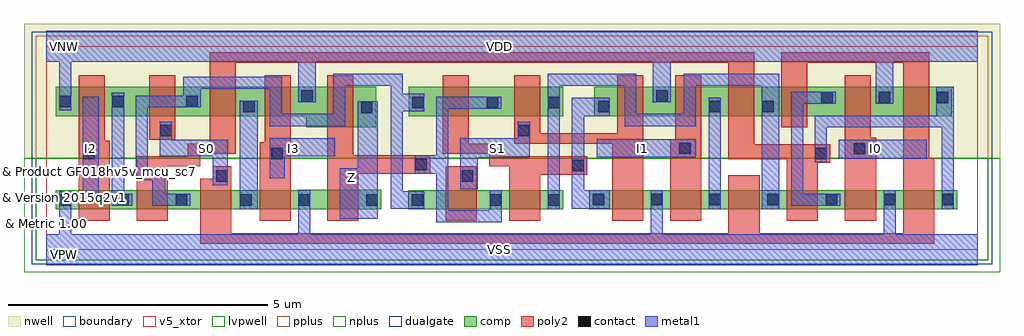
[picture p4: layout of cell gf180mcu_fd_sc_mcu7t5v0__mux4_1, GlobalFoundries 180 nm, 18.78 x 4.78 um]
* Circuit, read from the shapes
.subckt gf180mcu_fd_sc_mcu7t5v0__mux4_1 I0 I1 I2 I3 S0 S1 VDD VNW VSS Z
XM1 n1 I2 VSS VSUBS nfet_05v0 w=0.365u l=0.6u
XM2 n2 n3 n1 VSUBS nfet_05v0 w=0.365u l=0.6u
XM3 n4 S0 n2 VSUBS nfet_05v0 w=0.365u l=0.6u
XM4 VSS I3 n4 VSUBS nfet_05v0 w=0.365u l=0.6u
XM5 Z n5 VSS VSUBS nfet_05v0 w=0.38u l=0.6u
XM6 n5 S1 n2 VSUBS nfet_05v0 w=0.365u l=0.6u
XM7 n6 n7 n5 VSUBS nfet_05v0 w=0.365u l=0.6u
XM8 VSS S1 n7 VSUBS nfet_05v0 w=0.365u l=0.6u
XM9 n8 I1 VSS VSUBS nfet_05v0 w=0.365u l=0.6u
XM10 n6 S0 n8 VSUBS nfet_05v0 w=0.365u l=0.6u
XM11 n9 n3 n6 VSUBS nfet_05v0 w=0.365u l=0.6u
XM12 VSS I0 n9 VSUBS nfet_05v0 w=0.365u l=0.6u
XM13 n3 S0 VSS VSUBS nfet_05v0 w=0.365u l=0.6u
XM14 n1 I2 VDD VNW pfet_05v0 w=0.565u l=0.5u
XM15 n2 S0 n1 VNW pfet_05v0 w=0.565u l=0.5u
XM16 n4 n3 n2 VNW pfet_05v0 w=0.565u l=0.5u
XM17 VDD I3 n4 VNW pfet_05v0 w=0.565u l=0.5u
XM18 Z n5 VDD VNW pfet_05v0 w=0.78u l=0.5u
XM19 n5 n7 n2 VNW pfet_05v0 w=0.565u l=0.5u
XM20 n6 S1 n5 VNW pfet_05v0 w=0.565u l=0.5u
XM21 VDD S1 n7 VNW pfet_05v0 w=0.565u l=0.5u
XM22 n8 I1 VDD VNW pfet_05v0 w=0.565u l=0.5u
XM23 n6 n3 n8 VNW pfet_05v0 w=0.565u l=0.5u
XM24 n9 S0 n6 VNW pfet_05v0 w=0.565u l=0.5u
XM25 VDD I0 n9 VNW pfet_05v0 w=0.565u l=0.5u
XM26 n3 S0 VDD VNW pfet_05v0 w=0.565u l=0.5u
.ends

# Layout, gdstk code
import gdstk
lib = gdstk.Library(unit=1e-6, precision=1e-09)
def R(c, l, rs):  # rectangles x0, y0, x1, y1
    for r in rs: c.add(gdstk.rectangle(r[:2], r[2:], *l))
def A(c, l, x, y, w, h, nx, ny, dx, dy):  # array of equal rectangles
    R(c, l, [(x+i*dx, y+j*dy, x+i*dx+w, y+j*dy+h) for i in range(nx) for j in range(ny)])
def P(c, l, *ps):  # polygons
    for p in ps: c.add(gdstk.Polygon(p, *l))
boundary = (0, 0)
nwell = (21, 0)
comp = (22, 0)
poly2 = (30, 0)
pplus = (31, 0)
nplus = (32, 0)
contact = (33, 0)
metal1 = (34, 0)
dualgate = (55, 0)
v5_xtor = (112, 1)
lvpwell = (204, 0)

gf180mcu_fd_sc_mcu7t5v0_ = lib.new_cell('gf180mcu_fd_sc_mcu7t5v0__mux4_1')
R(gf180mcu_fd_sc_mcu7t5v0_, boundary, [(0,0,17.92,3.92)])
R(gf180mcu_fd_sc_mcu7t5v0_, nwell, [(-0.43,1.76,18.35,4.35)])
R(gf180mcu_fd_sc_mcu7t5v0_, comp, [(6.96,0.78,9.945,1.145), (10.445,0.78,17.525,1.145), (6.975,2.575,9.945,3.14), (10.545,2.575,17.425,3.14)])
P(gf180mcu_fd_sc_mcu7t5v0_, comp, [(5.005,2.36),(5.005,2.575),(0.18,2.575),(0.18,3.14),(6.345,3.14),(6.345,2.36)],
  [(0.18,0.78),(0.18,1.145),(5.005,1.145),(5.005,1.16),(6.445,1.16),(6.445,0.78)])
R(gf180mcu_fd_sc_mcu7t5v0_, poly2, [(7.685,0.56,8.285,1.605), (1.98,2.115,2.48,3.36)])
P(gf180mcu_fd_sc_mcu7t5v0_, poly2, [(0.62,0.56),(0.62,3.36),(1.12,3.36),(1.12,2.1),(1.22,2.1),(1.22,0.56)],
  [(4.105,0.56),(4.105,2.075),(4.205,2.075),(4.205,3.36),(4.705,3.36),(4.705,0.56)],
  [(5.405,0.56),(5.405,3.36),(5.905,3.36),(5.905,1.82),(7.385,1.82),(7.385,1.46),(6.005,1.46),(6.005,0.56)],
  [(8.905,0.56),(8.905,1.605),(8.525,1.605),(8.525,1.845),(7.625,1.845),(7.625,3.36),(8.125,3.36),(8.125,2.045),(8.765,2.045),(8.765,1.805),(10.41,1.805),(10.41,1.445),(9.505,1.445),(9.505,0.56)],
  [(10.885,0.56),(10.885,2.045),(9.005,2.045),(9.005,3.36),(9.505,3.36),(9.505,2.245),(10.985,2.245),(10.985,3.36),(11.485,3.36),(11.485,0.56)],
  [(12.005,0.56),(12.005,2.13),(12.105,2.13),(12.105,3.36),(12.605,3.36),(12.605,0.56)],
  [(1.74,0.56),(1.74,1.805),(2.72,1.805),(2.72,2.045),(3.14,2.045),(3.14,3.8),(13.625,3.8),(13.625,2.035),(15.085,2.035),(15.085,1.675),(14.845,1.675),(14.845,0.56),(14.245,0.56),(14.245,1.74),(13.125,1.74),(13.125,3.6),(3.64,3.6),(3.64,1.845),(2.96,1.845),(2.96,1.605),(2.34,1.605),(2.34,0.56)],
  [(15.365,0.56),(15.365,3.36),(15.865,3.36),(15.865,2.155),(15.965,2.155),(15.965,0.56)],
  [(2.96,0.12),(2.96,1.365),(3.2,1.365),(3.2,1.605),(3.56,1.605),(3.56,0.32),(13.125,0.32),(13.125,1.44),(13.725,1.44),(13.725,0.32),(16.485,0.32),(16.485,3.6),(14.645,3.6),(14.645,2.355),(14.145,2.355),(14.145,3.8),(16.985,3.8),(16.985,1.775),(17.085,1.775),(17.085,0.12)])
R(gf180mcu_fd_sc_mcu7t5v0_, pplus, [(-0.2,1.76,18.12,4.12)])
R(gf180mcu_fd_sc_mcu7t5v0_, nplus, [(-0.2,-0.2,18.12,1.76)])
A(gf180mcu_fd_sc_mcu7t5v0_, contact, 0.25, 0.85, 0.22, 0.22, 3, 1, 1.12, 0)
A(gf180mcu_fd_sc_mcu7t5v0_, contact, 10.515, 0.855, 0.22, 0.22, 7, 1, 1.12, 0)
R(gf180mcu_fd_sc_mcu7t5v0_, contact, [(3.735,0.85,3.955,1.07), (4.855,0.85,5.075,1.07), (6.155,0.85,6.375,1.07), (7.03,0.85,7.25,1.07), (8.535,0.85,8.755,1.07), (9.655,0.85,9.875,1.07), (3.27,1.315,3.49,1.535), (7.995,1.315,8.215,1.535), (10.12,1.515,10.34,1.735), (7.095,1.53,7.315,1.75), (0.71,1.745,0.93,1.965), (4.33,1.745,4.55,1.965), (14.795,1.745,15.015,1.965), (15.535,1.835,15.755,2.055), (12.18,1.845,12.4,2.065), (2.19,2.185,2.41,2.405), (9.075,2.185,9.295,2.405), (6.055,2.63,6.275,2.85), (3.79,2.645,4.01,2.865), (10.615,2.645,10.835,2.865), (12.755,2.645,12.975,2.865), (13.775,2.645,13.995,2.865), (7.045,2.725,7.265,2.945), (8.475,2.725,8.695,2.945), (9.655,2.725,9.875,2.945), (0.25,2.745,0.47,2.965), (1.27,2.745,1.49,2.965), (2.695,2.745,2.915,2.965), (14.91,2.82,15.13,3.04), (16.015,2.82,16.235,3.04), (17.135,2.82,17.355,3.04), (4.905,2.85,5.125,3.07), (11.735,2.85,11.955,3.07)])
R(gf180mcu_fd_sc_mcu7t5v0_, metal1, [(3.725,0.78,4.07,2.87), (12.75,0.78,12.98,2.925), (0.705,0.97,1.01,2.95), (15.25,1.75,16.94,2.12), (10.59,1.78,12.5,2.13)])
P(gf180mcu_fd_sc_mcu7t5v0_, metal1, [(1.26,0.845),(1.26,3.025),(1.495,3.025),(1.495,1.075),(1.65,1.075),(1.65,0.845)],
  [(3.2,1.24),(3.2,1.8),(2.185,1.8),(2.185,2.465),(2.415,2.465),(2.415,2.12),(3.495,2.12),(3.495,1.24)],
  [(4.3,1.375),(4.3,2.15),(5.55,2.15),(5.55,1.8),(4.585,1.8),(4.585,1.375)],
  [(5.65,0.6),(5.65,1.57),(5.99,1.57),(5.99,2.855),(6.38,2.855),(6.38,0.6)],
  [(6.63,0.79),(6.63,3.155),(5.75,3.155),(5.75,2.38),(4.3,2.38),(4.3,3.1),(2.975,3.1),(2.975,2.74),(1.955,2.74),(1.955,1.57),(2.29,1.57),(2.29,1.075),(2.77,1.075),(2.77,0.845),(2.04,0.845),(2.04,1.34),(1.725,1.34),(1.725,2.97),(2.635,2.97),(2.635,3.33),(4.53,3.33),(4.53,2.615),(5.52,2.615),(5.52,3.39),(6.86,3.39),(6.86,3.005),(7.27,3.005),(7.27,2.665),(6.86,2.665),(6.86,1.13),(7.27,1.13),(7.27,0.79)],
  [(7.5,0.53),(7.5,1.46),(7.09,1.46),(7.09,1.82),(7.5,1.82),(7.5,2.95),(8.755,2.95),(8.755,2.72),(7.73,2.72),(7.73,0.76),(8.53,0.76),(8.53,1.145),(8.76,1.145),(8.76,0.53)],
  [(7.96,1.165),(7.96,2.15),(9.07,2.15),(9.07,2.465),(9.3,2.465),(9.3,1.77),(8.3,1.77),(8.3,1.165)],
  [(10.11,0.795),(10.11,2.925),(10.84,2.925),(10.84,2.575),(10.35,2.575),(10.35,1.145),(10.84,1.145),(10.84,0.795)],
  [(9.65,0.78),(9.65,3.39),(11.355,3.39),(11.355,2.615),(12.265,2.615),(12.265,3.39),(14.1,3.39),(14.1,0.78),(13.77,0.78),(13.77,3.16),(12.495,3.16),(12.495,2.38),(11.125,2.38),(11.125,3.16),(9.88,3.16),(9.88,0.78)],
  [(14.33,0.85),(14.33,3.045),(15.19,3.045),(15.19,2.815),(14.56,2.815),(14.56,1.08),(15.275,1.08),(15.275,0.85)],
  [(17.23,0.78),(17.23,2.355),(15.02,2.355),(15.02,1.685),(14.79,1.685),(14.79,2.585),(17.125,2.585),(17.125,3.14),(17.46,3.14),(17.46,0.78)],
  [(0,-0.3),(0,0.3),(0.245,0.3),(0.245,1.13),(0.475,1.13),(0.475,0.3),(4.85,0.3),(4.85,1.16),(5.08,1.16),(5.08,0.3),(11.63,0.3),(11.63,1.145),(11.86,1.145),(11.86,0.3),(16.11,0.3),(16.11,1.145),(16.34,1.145),(16.34,0.3),(17.92,0.3),(17.92,-0.3)],
  [(0.245,2.685),(0.245,3.62),(0,3.62),(0,4.22),(17.92,4.22),(17.92,3.62),(16.295,3.62),(16.295,2.815),(15.955,2.815),(15.955,3.62),(12.015,3.62),(12.015,2.845),(11.67,2.845),(11.67,3.62),(5.185,3.62),(5.185,2.845),(4.845,2.845),(4.845,3.62),(0.475,3.62),(0.475,2.685)])
R(gf180mcu_fd_sc_mcu7t5v0_, dualgate, [(-0.28,-0.28,18.2,4.2)])
R(gf180mcu_fd_sc_mcu7t5v0_, v5_xtor, [(0,0,17.92,3.92)])
R(gf180mcu_fd_sc_mcu7t5v0_, lvpwell, [(-0.43,-0.43,18.35,1.76)])
gf180mcu_fd_sc_mcu7t5v0_.add(gdstk.Label('I0', (15.96,1.96), layer=34, texttype=10))
gf180mcu_fd_sc_mcu7t5v0_.add(gdstk.Label('VSS', (8.715,0), layer=34, texttype=10))
gf180mcu_fd_sc_mcu7t5v0_.add(gdstk.Label('VDD', (8.715,3.92), layer=34, texttype=10))
gf180mcu_fd_sc_mcu7t5v0_.add(gdstk.Label('I2', (0.84,1.96), layer=34, texttype=10))
gf180mcu_fd_sc_mcu7t5v0_.add(gdstk.Label('I1', (11.48,1.96), layer=34, texttype=10))
gf180mcu_fd_sc_mcu7t5v0_.add(gdstk.Label('S0', (3.08,1.96), layer=34, texttype=10))
gf180mcu_fd_sc_mcu7t5v0_.add(gdstk.Label('I3', (4.76,1.96), layer=34, texttype=10))
gf180mcu_fd_sc_mcu7t5v0_.add(gdstk.Label('S1', (8.68,1.96), layer=34, texttype=10))
gf180mcu_fd_sc_mcu7t5v0_.add(gdstk.Label('Z', (5.88,1.4), layer=34, texttype=10))
gf180mcu_fd_sc_mcu7t5v0_.add(gdstk.Label('& Vendor GLOBALFOUNDRIES', (0,2), layer=63, texttype=63))
gf180mcu_fd_sc_mcu7t5v0_.add(gdstk.Label('& Product GF018hv5v_mcu_sc7', (0,1.5), layer=63, texttype=63))
gf180mcu_fd_sc_mcu7t5v0_.add(gdstk.Label('& Version 2015q2v1', (0,1), layer=63, texttype=63))
gf180mcu_fd_sc_mcu7t5v0_.add(gdstk.Label('& Metric 1.00', (0,0.5), layer=63, texttype=63))
gf180mcu_fd_sc_mcu7t5v0_.add(gdstk.Label('VNW', (0.345,3.92), layer=21, texttype=10))
gf180mcu_fd_sc_mcu7t5v0_.add(gdstk.Label('VPW', (0.34,-0.085), layer=204, texttype=10))

lib.write_gds('gf180mcu_fd_sc_mcu7t5v0__mux4_1.gds')
